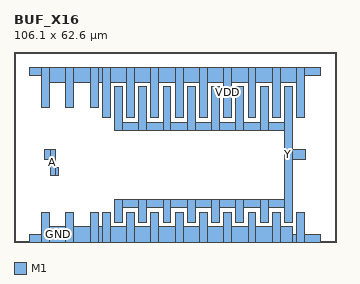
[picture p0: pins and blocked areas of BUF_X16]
MACRO BUF_X16
  CLASS CORE ;
  ORIGIN 0 0 ;
  SIZE 106.100 BY 62.600 ;
  SYMMETRY X Y ;
  SITE TR1um_site ;
  PIN VDD
    DIRECTION INOUT ;
    USE POWER ;
    PORT
      LAYER M1 ;
        RECT 5.000 55.000 9.100 57.600 ;
      LAYER M1 ;
        RECT 9.100 44.400 11.700 57.600 ;
      LAYER M1 ;
        RECT 11.700 52.600 17.100 57.600 ;
      LAYER M1 ;
        RECT 17.100 44.400 19.700 57.600 ;
      LAYER M1 ;
        RECT 19.700 52.600 25.100 57.600 ;
      LAYER M1 ;
        RECT 25.100 44.400 27.700 57.600 ;
      LAYER M1 ;
        RECT 27.700 52.600 29.100 57.600 ;
      LAYER M1 ;
        RECT 29.100 41.000 31.700 57.600 ;
      LAYER M1 ;
        RECT 31.700 52.600 37.100 57.600 ;
      LAYER M1 ;
        RECT 37.100 41.000 39.700 57.600 ;
      LAYER M1 ;
        RECT 39.700 52.600 45.100 57.600 ;
      LAYER M1 ;
        RECT 45.100 41.000 47.700 57.600 ;
      LAYER M1 ;
        RECT 47.700 52.600 53.100 57.600 ;
      LAYER M1 ;
        RECT 53.100 41.000 55.700 57.600 ;
      LAYER M1 ;
        RECT 55.700 52.600 61.100 57.600 ;
      LAYER M1 ;
        RECT 61.100 41.000 63.700 57.600 ;
      LAYER M1 ;
        RECT 63.700 52.600 69.100 57.600 ;
      LAYER M1 ;
        RECT 69.100 41.000 71.700 57.600 ;
      LAYER M1 ;
        RECT 71.700 52.600 77.100 57.600 ;
      LAYER M1 ;
        RECT 77.100 41.000 79.700 57.600 ;
      LAYER M1 ;
        RECT 79.700 52.600 85.100 57.600 ;
      LAYER M1 ;
        RECT 85.100 41.000 87.700 57.600 ;
      LAYER M1 ;
        RECT 87.700 52.600 93.100 57.600 ;
      LAYER M1 ;
        RECT 93.100 41.000 95.700 57.600 ;
      LAYER M1 ;
        RECT 95.700 55.000 101.100 57.600 ;
    END
  END VDD
  PIN Y
    DIRECTION OUTPUT ;
    USE SIGNAL ;
    PORT
      LAYER M1 ;
        RECT 33.100 6.400 35.700 14.000 ;
      LAYER M1 ;
        RECT 33.100 36.800 35.700 51.200 ;
      LAYER M1 ;
        RECT 35.700 11.400 41.100 14.000 ;
      LAYER M1 ;
        RECT 35.700 36.800 41.100 39.400 ;
      LAYER M1 ;
        RECT 41.100 6.400 43.700 14.000 ;
      LAYER M1 ;
        RECT 41.100 36.800 43.700 51.200 ;
      LAYER M1 ;
        RECT 43.700 11.400 49.100 14.000 ;
      LAYER M1 ;
        RECT 43.700 36.800 49.100 39.400 ;
      LAYER M1 ;
        RECT 49.100 6.400 51.700 14.000 ;
      LAYER M1 ;
        RECT 49.100 36.800 51.700 51.200 ;
      LAYER M1 ;
        RECT 51.700 11.400 57.100 14.000 ;
      LAYER M1 ;
        RECT 51.700 36.800 57.100 39.400 ;
      LAYER M1 ;
        RECT 57.100 6.400 59.700 14.000 ;
      LAYER M1 ;
        RECT 57.100 36.800 59.700 51.200 ;
      LAYER M1 ;
        RECT 59.700 11.400 65.100 14.000 ;
      LAYER M1 ;
        RECT 59.700 36.800 65.100 39.400 ;
      LAYER M1 ;
        RECT 65.100 6.400 67.700 14.000 ;
      LAYER M1 ;
        RECT 65.100 36.800 67.700 51.200 ;
      LAYER M1 ;
        RECT 67.700 11.400 73.100 14.000 ;
      LAYER M1 ;
        RECT 67.700 36.800 73.100 39.400 ;
      LAYER M1 ;
        RECT 73.100 6.400 75.700 14.000 ;
      LAYER M1 ;
        RECT 73.100 36.800 75.700 51.200 ;
      LAYER M1 ;
        RECT 75.700 11.400 81.100 14.000 ;
      LAYER M1 ;
        RECT 75.700 36.800 81.100 39.400 ;
      LAYER M1 ;
        RECT 81.100 6.400 83.700 14.000 ;
      LAYER M1 ;
        RECT 81.100 36.800 83.700 51.200 ;
      LAYER M1 ;
        RECT 83.700 11.400 89.100 14.000 ;
      LAYER M1 ;
        RECT 83.700 36.800 89.100 39.400 ;
      LAYER M1 ;
        RECT 89.100 6.400 91.700 51.200 ;
      LAYER M1 ;
        RECT 91.700 27.100 96.000 30.500 ;
    END
  END Y
  PIN A
    DIRECTION INPUT ;
    USE SIGNAL ;
    PORT
      LAYER M1 ;
        RECT 10.100 27.100 11.900 30.500 ;
      LAYER M1 ;
        RECT 11.900 22.000 13.700 30.500 ;
      LAYER M1 ;
        RECT 13.700 22.000 14.500 24.600 ;
    END
  END A
  PIN GND
    DIRECTION INOUT ;
    USE GROUND ;
    PORT
      LAYER M1 ;
        RECT 5.000 0.000 9.100 2.600 ;
      LAYER M1 ;
        RECT 9.100 0.000 11.700 9.800 ;
      LAYER M1 ;
        RECT 11.700 0.000 17.100 5.000 ;
      LAYER M1 ;
        RECT 17.100 0.000 19.700 9.800 ;
      LAYER M1 ;
        RECT 19.700 0.000 25.100 5.000 ;
      LAYER M1 ;
        RECT 25.100 0.000 27.700 9.800 ;
      LAYER M1 ;
        RECT 27.700 0.000 29.100 5.000 ;
      LAYER M1 ;
        RECT 29.100 0.000 31.700 9.800 ;
      LAYER M1 ;
        RECT 31.700 0.000 37.100 5.000 ;
      LAYER M1 ;
        RECT 37.100 0.000 39.700 9.800 ;
      LAYER M1 ;
        RECT 39.700 0.000 45.100 5.000 ;
      LAYER M1 ;
        RECT 45.100 0.000 47.700 9.800 ;
      LAYER M1 ;
        RECT 47.700 0.000 53.100 5.000 ;
      LAYER M1 ;
        RECT 53.100 0.000 55.700 9.800 ;
      LAYER M1 ;
        RECT 55.700 0.000 61.100 5.000 ;
      LAYER M1 ;
        RECT 61.100 0.000 63.700 9.800 ;
      LAYER M1 ;
        RECT 63.700 0.000 69.100 5.000 ;
      LAYER M1 ;
        RECT 69.100 0.000 71.700 9.800 ;
      LAYER M1 ;
        RECT 71.700 0.000 77.100 5.000 ;
      LAYER M1 ;
        RECT 77.100 0.000 79.700 9.800 ;
      LAYER M1 ;
        RECT 79.700 0.000 85.100 5.000 ;
      LAYER M1 ;
        RECT 85.100 0.000 87.700 9.800 ;
      LAYER M1 ;
        RECT 87.700 0.000 91.700 5.000 ;
      LAYER M1 ;
        RECT 91.700 0.000 93.100 2.600 ;
      LAYER M1 ;
        RECT 93.100 0.000 95.700 9.800 ;
      LAYER M1 ;
        RECT 95.700 0.000 101.100 2.600 ;
    END
  END GND
END BUF_X16
